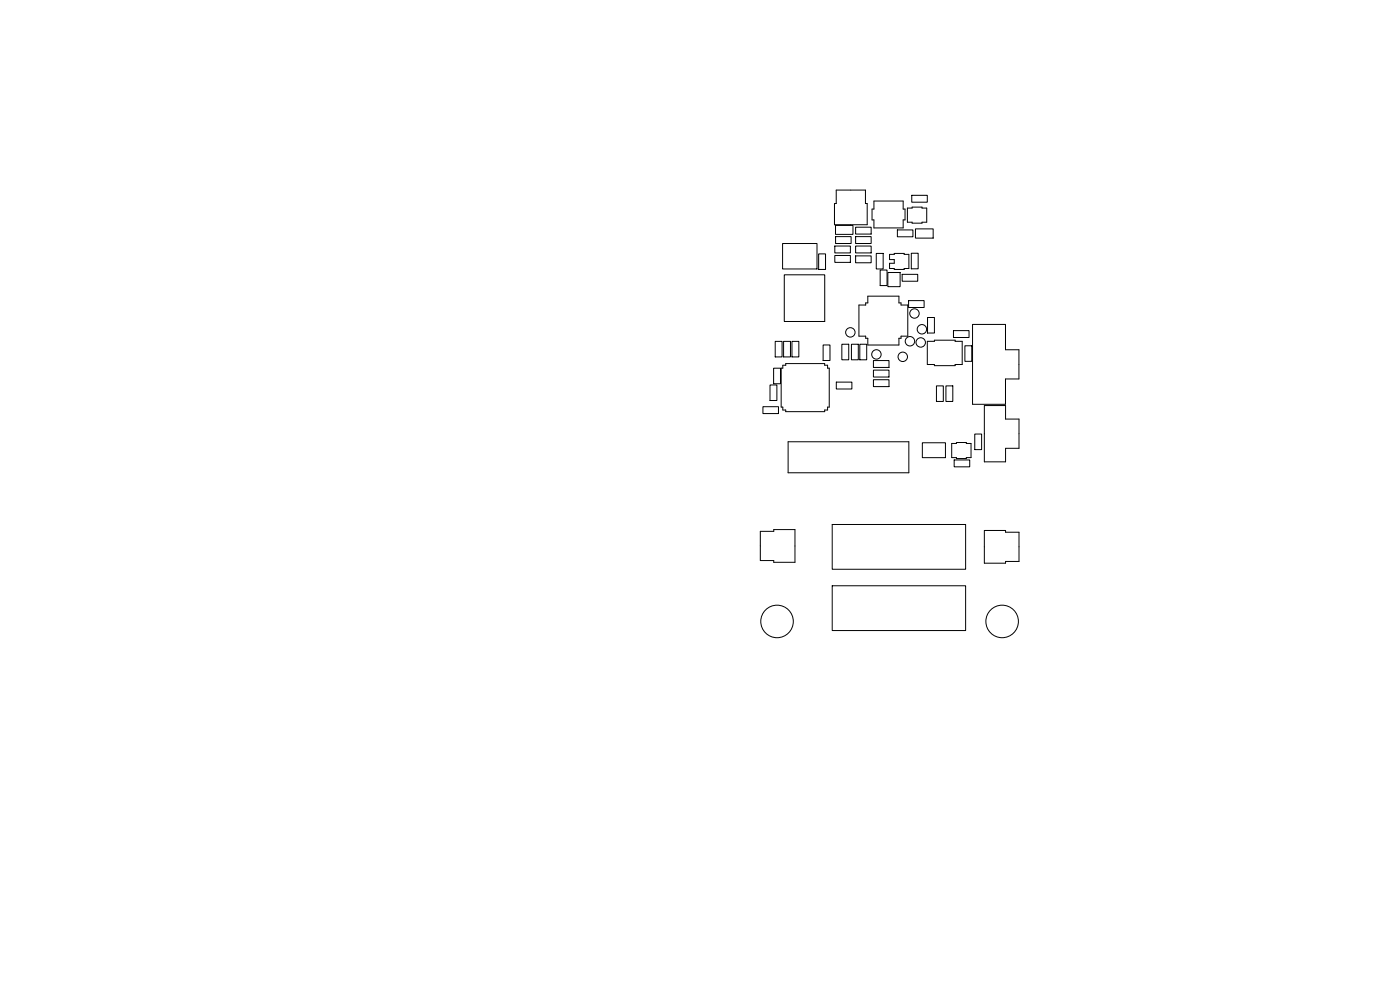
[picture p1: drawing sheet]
<svg xmlns="http://www.w3.org/2000/svg" width="297mm" height="210mm" viewBox="0 0 297 210" stroke-linecap="round" stroke-linejoin="round" font-family="sans-serif">
<g fill="none" stroke="#000" stroke-width=".21">
<path d="M166 51.7h7.3v5.4h-7.3zM166.4 58.3h8.6v9.9h-8.6zM173.7 53.9h1.4v3.3h-1.4zM177.1 52.2h3.3v1.5h-3.3zM177.1 54.2h3.3v1.5h-3.3zM177.2 47.8h3.7v1.9h-3.7zM177.3 50.2h3.3v1.5h-3.3zM177.4 40.3h6.2v2.9h.4v4.5h-7v-4.5h.4zM181.5 52.2h3.3v1.5h-3.3zM181.5 48.2h3.3v1.5h-3.3zM181.5 50.2h3.3v1.5h-3.3zM181.5 54.3h3.3v1.4h-3.3z"/>
<path d="M185.4 42.7h6.2v1.7h.4v2.3h-.4v1.7h-6.2v-1.7h-.4v-2.3h.4zM185.9 53.8h1.5v3.3h-1.5zM186.7 57.3h1.5v3.3h-1.5zM188.4 57.8h2.6v3h-2.6zM188.7 54h1v-.2h2.1v.2h1v3h-1v.2h-2.1v-.2h-1v-1.2h1v-.7h-1zM190.4 48.8h3.3v1.4h-3.3zM191.4 58.2h3.3v1.5h-3.3zM192.5 44.1h1v-.2h2.1v.2h1v3h-1v.2h-2.1v-.2h-1zM193.3 53.7h1.5v3.3h-1.5zM193.4 41.4h3.3v1.5h-3.3zM194.2 48.6h3.8v1.9h-3.8zM164.1 78.1h1.5v3.3h-1.5z"/>
<path d="M164.5 72.4h1.4v3.3h-1.4zM166.1 77.5h.6v-.4h8.2v.4h.7v.6h.3v8.3h-.3v.6h-.7v.3h-8.2v-.3h-.6v-.6h-.4v-8.3h.4zM166.2 72.4h1.5v3.3h-1.5zM168 72.4h1.5v3.3h-1.5zM174.6 73.2h1.5v3.3h-1.5zM178.6 73h1.5v3.3h-1.5zM180.6 73h1.5v3.3h-1.5zM182.2 64.7h1.5v-.4h.4v-1.5h6.6v1.5h.5v.4h1.4v6.6h-1.4v.5h-.5v1.4h-6.6v-1.4h-.4v-.5h-1.5zM182.4 73h1.5v3.3h-1.5zM185.3 78.5h3.3v1.5h-3.3zM185.3 76.5h3.3v1.4h-3.3zM192.8 63.8h3.3v1.4h-3.3z"/>
<path d="M196.7 72.4h1.5v-.2h4.4v.2h1.5v4.9h-1.5v.3h-4.4v-.3h-1.5zM196.8 67.4h1.4v3.3h-1.4zM202.3 70.1h3.3v1.5h-3.3zM204.7 73.4h1.5v3.3h-1.5zM206.3 68.8h7v5.4h2.9v6.2h-2.9v5.4h-7zM161.8 86.3h3.3v1.4h-3.3zM163.4 81.7h1.4v3.3h-1.4zM167.2 93.7h25.6v6.6h-25.6zM177.4 81.1h3.3v1.4h-3.3zM185.3 80.6h3.3v1.4h-3.3zM195.7 93.9h4.9v3.2h-4.9zM198.7 81.9h1.4v3.3h-1.4z"/>
<path d="M200.7 81.9h1.4v3.3h-1.4zM201.9 94.1h1v-.2h2.1v.2h1v3h-1v.2h-2.1v-.2h-1zM202.4 97.6h3.3v1.4h-3.3zM206.8 92.1h1.4v3.3h-1.4zM208.8 86h4.5v2.9h2.9v6.2h-2.9v2.9h-4.5zM161.3 112.7h2.8v-.4h4.5v7h-4.5v-.4h-2.8zM176.6 111.3h28.3v9.5h-28.3zM208.8 112.5h4.5v.4h2.9v6.2h-2.9v.4h-4.5zM176.6 124.3h28.3v9.5h-28.3z"/>
<circle cx="180.4" cy="70.5" r="1"/>
<circle cx="185.9" cy="75.2" r="1"/>
<circle cx="191.5" cy="75.7" r="1"/>
<circle cx="193" cy="72.4" r="1"/>
<circle cx="194" cy="66.5" r="1"/>
<circle cx="195.3" cy="72.6" r="1"/>
<circle cx="195.6" cy="69.8" r="1"/>
<circle cx="164.8" cy="131.8" r="3.5"/>
<circle cx="212.6" cy="131.8" r="3.5"/>
</g>
</svg>
